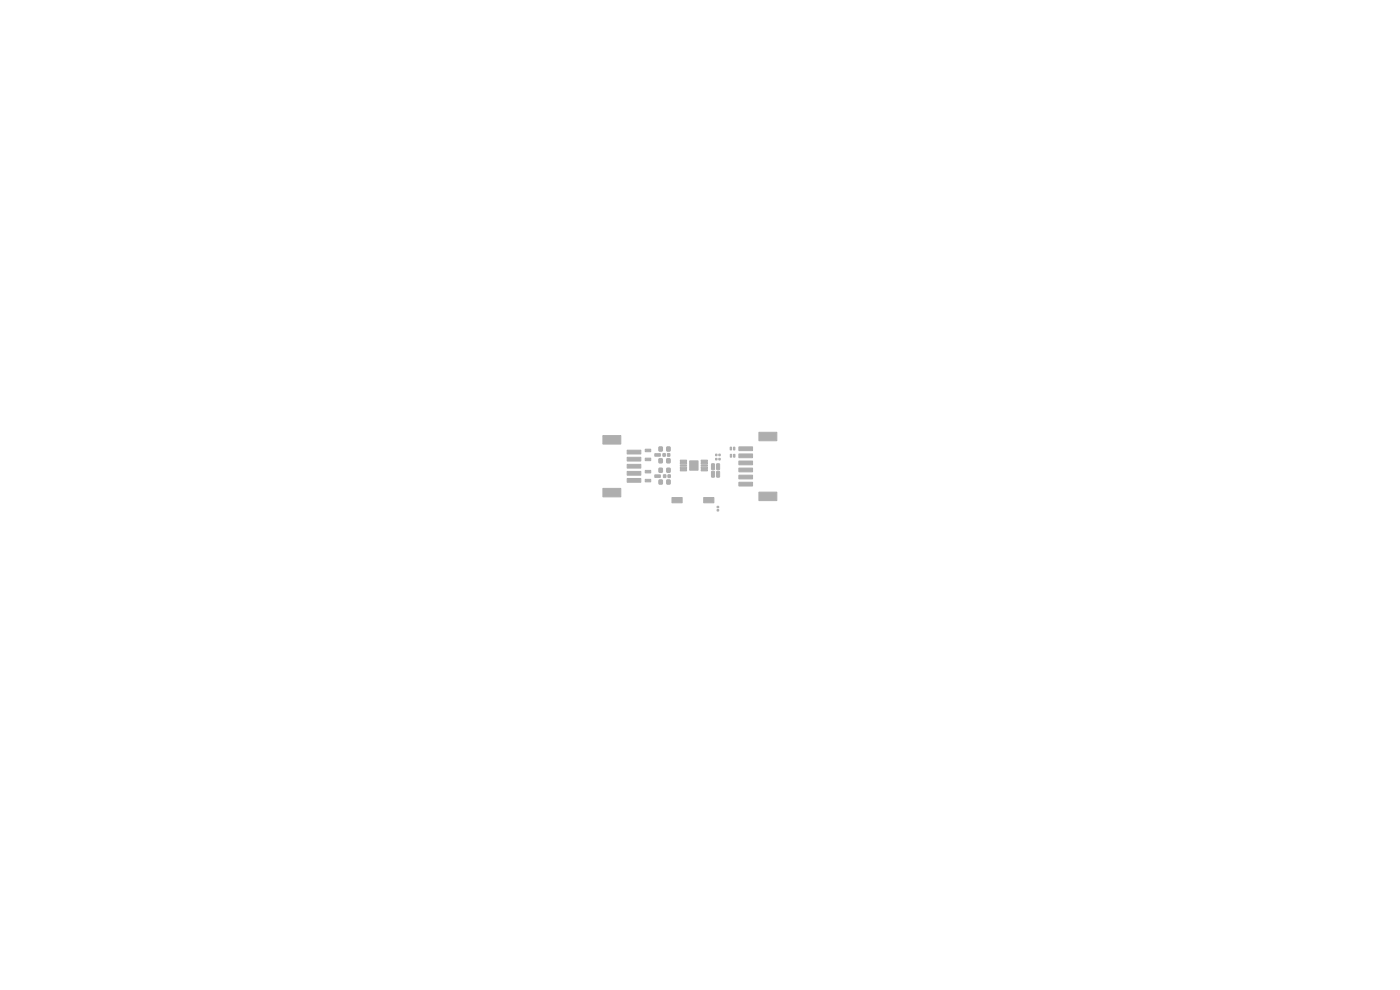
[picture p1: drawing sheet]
<svg xmlns="http://www.w3.org/2000/svg" width="297mm" height="210mm" viewBox="0 0 297 210" stroke-linecap="round" stroke-linejoin="round" font-family="sans-serif">
<g fill="#bbaaa4" stroke="#bbaaa4" stroke-width=".21">
<path d="M154.9 96.4h.3v.6h-.3z"/>
<path d="M155.6 96.4h.3v.6h-.3z"/>
<path d="M154.9 94.8h.3v.6h-.3z"/>
<path d="M155.6 94.8h.3v.6h-.3z"/>
<path d="M136.9 95.3h1.2v.5h-1.2z"/>
<path d="M136.9 97.2h1.2v.5h-1.2z"/>
<path d="M138.9 96.2h1.2v.6h-1.2z"/>
<path d="M139.8 97.3h.7v.9h-.7z"/>
<path d="M141.5 97.3h.6v.9h-.6z"/>
<path d="M141.7 100.7h.5v.6h-.5z"/>
<path d="M140.8 100.7h.4v.6h-.4z"/>
<path d="M139.8 94.8h.7v.9h-.7z"/>
<path d="M141.5 94.8h.6v.9h-.6z"/>
<path d="M152.5 97.2h.3v.4h-.3z"/>
<path d="M151.8 97.2h.3v.4h-.3z"/>
<path d="M151.8 96.3h.3v.4h-.3z"/>
<path d="M152.5 96.3h.3v.4h-.3z"/>
<path d="M149.3 105.5h2.1v1.2h-2.1z"/>
<path d="M142.6 105.5h2.1v1.2h-2.1z"/>
<path d="M144.3 97.6h1.4v.3h-1.4z"/>
<path d="M144.3 98.1h1.4v.3h-1.4z"/>
<path d="M144.3 98.6h1.4v.3h-1.4z"/>
<path d="M144.3 99.1h1.4v.3h-1.4z"/>
<path d="M144.3 99.6h1.4v.3h-1.4z"/>
<path d="M148.7 99.6h1.4v.3h-1.4z"/>
<path d="M148.7 99.1h1.4v.3h-1.4z"/>
<path d="M148.7 98.6h1.4v.3h-1.4z"/>
<path d="M148.7 98.1h1.4v.3h-1.4z"/>
<path d="M148.7 97.6h1.4v.3h-1.4z"/>
<path d="M146.3 97.8h1.8v1.9h-1.8z"/>
<path d="M152.1 107.4h.4v.3h-.4z"/>
<path d="M152.1 108.1h.4v.3h-.4z"/>
<path d="M136.9 99.8h1.2v.5h-1.2z"/>
<path d="M136.9 101.7h1.2v.5h-1.2z"/>
<path d="M138.9 100.7h1.2v.6h-1.2z"/>
<path d="M151 100l.6 .1-.1 1.1-.6-.1z"/>
<path d="M152.1 100l.6 .1-.1 1.1-.6-.1z"/>
<path d="M156.8 102.3h2.8v.8h-2.8z"/>
<path d="M156.8 100.8h2.8v.8h-2.8z"/>
<path d="M156.8 99.3h2.8v.8h-2.8z"/>
<path d="M156.8 97.8h2.8v.8h-2.8z"/>
<path d="M156.8 96.3h2.8v.8h-2.8z"/>
<path d="M156.8 94.8h2.8v.8h-2.8z"/>
<path d="M161 104.4h3.8v1.8h-3.8z"/>
<path d="M161 91.7h3.8v1.8h-3.8z"/>
<path d="M141.5 101.8h.7v.9h-.7z"/>
<path d="M139.8 101.8h.7v.9h-.7z"/>
<path d="M139.8 99.3h.7v.9h-.7z"/>
<path d="M141.5 99.3h.7v.9h-.7z"/>
<path d="M141.6 96.2h.5v.6h-.5z"/>
<path d="M140.7 96.2h.4v.6h-.4z"/>
<path d="M151 98.4l.6 .1-.1 1.1-.6-.1z"/>
<path d="M152.1 98.4l.6 .1-.1 1.1-.6-.1z"/>
<path d="M133.1 95.5h2.8v.8h-2.8z"/>
<path d="M133.1 97h2.8v.8h-2.8z"/>
<path d="M133.1 98.5h2.8v.8h-2.8z"/>
<path d="M133.1 100h2.8v.8h-2.8z"/>
<path d="M133.1 101.5h2.8v.8h-2.8z"/>
<path d="M127.9 92.4h3.8v1.8h-3.8z"/>
<path d="M127.9 103.6h3.8v1.8h-3.8z"/>
</g>
</svg>
